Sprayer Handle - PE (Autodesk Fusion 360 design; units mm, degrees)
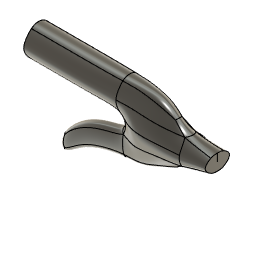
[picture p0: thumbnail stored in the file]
form "Form1"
